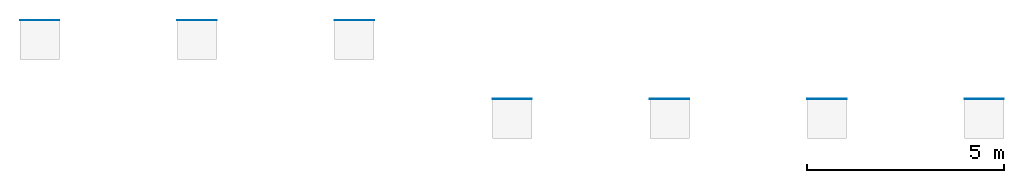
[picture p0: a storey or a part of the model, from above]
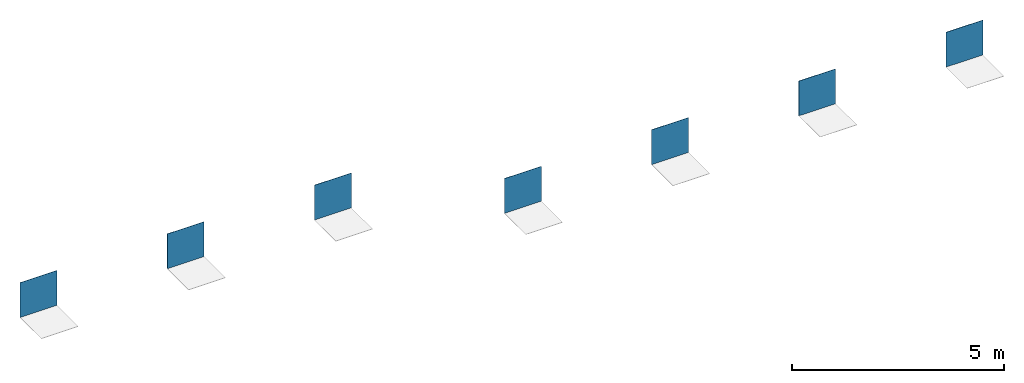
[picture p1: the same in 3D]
Properties of the parts of a building model (IFC2X3)

# File
Description: ViewDefinition [CoordinationView_V2.0]
Time: 2025-06-20T12:25:37
Written by: The EXPRESS Data Manager Version 5.02.0100.07 : 28 Aug 2013
Made in: 21.1.90.15 - Exporter 21.1.90.15 - Alternate UI 21.1.90.15
Comment: STEP Physical File produced by: The EXPRESS Data Manager Version 5.02.0100.07 : 28 Aug 2013 * Module: EDMstepFileFactory/EDMstandAlone * Creation date: Fri Jun 20 12:25:37 2025 * Host: STB002 * Database: C:\Users\LARISS~1\AppData\Local\Temp\234e31d9-e186-458c-9206-d387dea7a233\789adf32-d584-4b62-985c-cae58ec91f2d\ifc * Database version: 5507 * Database creation date: Fri Jun 20 12:25:37 2025 * Schema: IFC2X3 * Model: DataRepository.ifc * Model creation date: Fri Jun 20 12:25:37 2025 * Header model: DataRepository.ifc_HeaderModel * Header model creation date: Fri Jun 20 12:25:37 2025 * EDMuser: sdai-user * EDMgroup: sdai-group * License ID and type: 5605 : Permanent license. Expiry date: * EDMstepFileFactory options: 020000

# IfcSite, Default
RefLatitude: 42, 24, 53, 508911; RefLongitude: -71, -15, -29, -58837; RefElevation: 0 mm
Pset_ProductRequirements - Category: Project Information

# IfcBuilding
Pset_BuildingCommon - NumberOfStoreys: 1
Pset_ProductRequirements - Category: Project Information

# IfcBuildingStorey: Level:Level 1, Level 1
LongName: Level 1; Elevation: 0 mm
Pset_AirSideSystemInformation - Name: Level 1
Pset_ProductRequirements - Name: Level 1; Category: Levels

# IfcCovering: Floor:REVIGRÉS-LOCUS-DECOR-16,5X19-SOFT GRIP-HEXA FLOW BONE, Floor:REVIGRÉS-LOCUS-DECOR-16,5X19-SOFT GRIP-HEXA FLOW BONE:112826
In: Level 1
Type - PredefinedType: CLADDING; Material: REVIGRÉS-LOCUS-DECOR-16,5x19-SOFT GRIP-HEXA FLOW BONE 8.5 mm
Type - Pset_CoveringCommon - Material: Grés porcelânico
Type - Pset_ElementShading - Roughness: 304.8 mm
Type - Pset_ManufacturerTypeInformation - Manufacturer: REVIGRÉS
Type - Pset_ProductRequirements - Category: Floors
Type - IFC.REVIGRÉS-Dados do fabricante-Floor Covering - FabricanteURL: https://www.revigres.pt/; ReferenciaModelo: Locus; Acabamento: SOFT; Material: Grés porcelânico; IdentificadorDoOperadorEconomico: 501840856; GLNFabricante: https://www.revigres.pt/colecoes/locus; UrlFabricanteArtigo: https://www.revigres.pt/colecoes/locus; PaisOrigem: Portugal
Type - IFC.REVIGRÉS-Dados de desempenho-Floor Covering - Rectilinearidade: ± 0.2% máx.± 0.8 mm; Ortogonalidade: ± 0.2% máx.± 1.5 mm; PlanaridadeDaSuperficie: ± 0.3% máx. ± 1.8 mm; QualidadeDaSuperficie: Cumpre; AbsorcaoDeAgua: < 0.05%; CargaDeRuptura: > 45 N/mm²; ModuloDeRuptura: > 45 N/mm²; ResistenciaAFlexao: > 2000 N; ResistenciaAAbrasaoProfunda: < 120 mm³; ResistenciaAAbrasaoVidrados: ≤ 8,0x10-6 °C-1; DilatacaoTermicaLinear: ≤ 8,0x10-6 °C-1; ResistenciaAoChoqueTermico: Resiste; ResistenciaAFendilhagem: Cumpre; DurabilidadeInterior: Cumpre; DurabilidadeResistenciaAoGeloDegelo: Resiste; ResistenciaAoImpacto: R11; ResistenciaAoEscorregamentoDIN51130: R11; ResistenciaAoEscorregamentoDIN51097: A; ResistenciaAoEscorregamentoENV51097: A; ResistenciaAoEscorregamentoENV12633: Class 2; ResistenciaAoEscorregamentoBS7976: > 36; ResistenciaAoEscorregamentoEN177: ≥0,42; ResistenciaAoEscorregamentoANSIA1371: ≥0,42; ResistenciaAoDeslizamentoENV12633: Class 2; ResistenciaAoDeslizamentoBS7976: > 36; ResistenciaDaAderenciaArgamassas: Class A1FL/ Class A1; ResistenciaAsManchas: Class 5; ResistenciaAProdutosDomesticosDeLimpeza: 0; LibertacaoDeCadmio: 0; LibertacaoDeChumbo: 0
Type - IFC.REVIGRÉS-Dados de especificação-Floor Covering - VariacaoTonalidade: 3; NivelDeTrafego: 5; EPavimento: Sim; ERevestimento: Sim; EExterno: Sim
Type - IFC.REVIGRÉS-Dados geométricos-Floor Covering - AlturaNominal: 8.5 mm; ComprimentoNominal: 16.5 mm; LarguraNominal: 19 mm
Type - IFC.REVIGRÉS-Dados de sustentabilidade-Floor Covering - ItemEParcialmenteReciclado: 0; EnergiaTermicaExportada: 0; VolumeTotalDeResiduosRadioactivosEliminados: 0; ItemENovo: Sim; ItemEReciclado: Não; VidaÚtilEsperada: 50; SubstanciasPerigosas: Não; PotencialDeEsgotamentoAbioticoDosRecursosNaoFosseisMineraisEMetais: 0.000701; PotencialDeAquecimentoGlobalBiogenico: -0.48; CombustiveisFosseisComPotencialDeAquecimentoGlobal: 13.9; PotencialDeAquecimentoGlobalUsoDoSoloEMudancaDeUsoDoSolo: 0.0246; PotencialDeEutrofizacaoFraccaoDeNutrientesQueAtingemOCompartimentoFinalDeAguaDoce: 0.000189; PotencialDeEutrofizacaoFraccaoDeNutrientesQueAtingemOCompartimentoFinalMarinho: 0.0122; EnergiaRecuperada: 0.00739; ConsumoDeAguaDoce: 0.113; UtilizacaoLiquidaDeAguaDoce: 0.113; ResiduosPerigososEliminados: 0.00221; ResiduosNaoPerigososEliminados: 1.83; MassaTotalDeResiduosRadioactivosEliminados: 0.000394; EnergiaElectricaExportada: 1.55; MateriaisParaRecuperacaoDeEnergia: 0.00739; MateriaisParaReciclagem: 0.0253; UnidadeEPD: 1 m²
Type - IFC.REVIGRÉS-Dados gerais-Floor Covering - Nome: REVIGRÉS-LOCUS-DECOR- 16,5X19-SOFT GRIP-HEXA FLOW BONE; TipoProduto: Prensado a seco: grupo BIa UGL | Grés porcelânico técnico; NumeroDeRegistoDAP: EPD-REV-20240006-CCC1-EN; ReferenciaDAP: -; UrlDOP: -
Classification: C3010 (Uniformat)
Pset_CoveringCommon - TotalThickness: 8.5 mm
IFC.REVIGRÉS-Dados do fabricante-Floor Covering - Type: Floor: REVIGRÉS-LOCUS-DECOR-16,5X19-SOFT GRIP-HEXA FLOW BONE
IFC.REVIGRÉS-Dados de desempenho-Floor Covering - Type: Floor: REVIGRÉS-LOCUS-DECOR-16,5X19-SOFT GRIP-HEXA FLOW BONE
IFC.REVIGRÉS-Dados de especificação-Floor Covering - Type: Floor: REVIGRÉS-LOCUS-DECOR-16,5X19-SOFT GRIP-HEXA FLOW BONE
IFC.REVIGRÉS-Dados geométricos-Floor Covering - Type: Floor: REVIGRÉS-LOCUS-DECOR-16,5X19-SOFT GRIP-HEXA FLOW BONE
IFC.REVIGRÉS-Dados de sustentabilidade-Floor Covering - Type: Floor: REVIGRÉS-LOCUS-DECOR-16,5X19-SOFT GRIP-HEXA FLOW BONE

# IfcCovering: Floor:REVIGRÉS-LOCUS-DECOR-16,5X19-SOFT GRIP-HEXA FLOW SMOG, Floor:REVIGRÉS-LOCUS-DECOR-16,5X19-SOFT GRIP-HEXA FLOW SMOG:112834
In: Level 1
Type - PredefinedType: CLADDING; Material: REVIGRÉS-LOCUS-DECOR-16,5x19-SOFT GRIP-HEXA FLOW SMOG 8.5 mm
Type - Pset_CoveringCommon - Material: Grés porcelânico
Type - Pset_ElementShading - Roughness: 304.8 mm
Type - Pset_ManufacturerTypeInformation - Manufacturer: REVIGRÉS
Type - Pset_ProductRequirements - Category: Floors
Type - IFC.REVIGRÉS-Dados do fabricante-Floor Covering - FabricanteURL: https://www.revigres.pt/; ReferenciaModelo: Locus; Acabamento: SOFT; Material: Grés porcelânico; IdentificadorDoOperadorEconomico: 501840856; GLNFabricante: https://www.revigres.pt/colecoes/locus; UrlFabricanteArtigo: https://www.revigres.pt/colecoes/locus; PaisOrigem: Portugal
Type - IFC.REVIGRÉS-Dados de desempenho-Floor Covering - Rectilinearidade: ± 0.2% máx.± 0.8 mm; Ortogonalidade: ± 0.2% máx.± 1.5 mm; PlanaridadeDaSuperficie: ± 0.3% máx. ± 1.8 mm; QualidadeDaSuperficie: Cumpre; AbsorcaoDeAgua: < 0.05%; CargaDeRuptura: > 45 N/mm²; ModuloDeRuptura: > 45 N/mm²; ResistenciaAFlexao: > 2000 N; ResistenciaAAbrasaoProfunda: < 120 mm³; ResistenciaAAbrasaoVidrados: ≤ 8,0x10-6 °C-1; DilatacaoTermicaLinear: ≤ 8,0x10-6 °C-1; ResistenciaAoChoqueTermico: Resiste; ResistenciaAFendilhagem: Cumpre; DurabilidadeInterior: Cumpre; DurabilidadeResistenciaAoGeloDegelo: Resiste; ResistenciaAoImpacto: R11; ResistenciaAoEscorregamentoDIN51130: R11; ResistenciaAoEscorregamentoDIN51097: A; ResistenciaAoEscorregamentoENV51097: A; ResistenciaAoEscorregamentoENV12633: Class 2; ResistenciaAoEscorregamentoBS7976: > 36; ResistenciaAoEscorregamentoEN177: ≥0,42; ResistenciaAoEscorregamentoANSIA1371: ≥0,42; ResistenciaAoDeslizamentoENV12633: Class 2; ResistenciaAoDeslizamentoBS7976: > 36; ResistenciaDaAderenciaArgamassas: Class A1FL/ Class A1; ResistenciaAsManchas: Class 5; ResistenciaAProdutosDomesticosDeLimpeza: 0; LibertacaoDeCadmio: 0; LibertacaoDeChumbo: 0
Type - IFC.REVIGRÉS-Dados de especificação-Floor Covering - VariacaoTonalidade: 3; NivelDeTrafego: 5; EPavimento: Sim; ERevestimento: Sim; EExterno: Sim
Type - IFC.REVIGRÉS-Dados geométricos-Floor Covering - AlturaNominal: 8.5 mm; ComprimentoNominal: 16.5 mm; LarguraNominal: 19 mm
Type - IFC.REVIGRÉS-Dados de sustentabilidade-Floor Covering - EnergiaTermicaExportada: 0; VolumeTotalDeResiduosRadioactivosEliminados: 0; ItemENovo: Sim; ItemEParcialmenteReciclado: 0.29; ItemEReciclado: Sim; VidaÚtilEsperada: 50; SubstanciasPerigosas: Não; PotencialDeEsgotamentoAbioticoDosRecursosNaoFosseisMineraisEMetais: 0.000701; PotencialDeAquecimentoGlobalBiogenico: -0.48; CombustiveisFosseisComPotencialDeAquecimentoGlobal: 13.9; PotencialDeAquecimentoGlobalUsoDoSoloEMudancaDeUsoDoSolo: 0.0246; PotencialDeEutrofizacaoFraccaoDeNutrientesQueAtingemOCompartimentoFinalDeAguaDoce: 0.000189; PotencialDeEutrofizacaoFraccaoDeNutrientesQueAtingemOCompartimentoFinalMarinho: 0.0122; EnergiaRecuperada: 0.00739; ConsumoDeAguaDoce: 0.113; UtilizacaoLiquidaDeAguaDoce: 0.113; ResiduosPerigososEliminados: 0.00221; ResiduosNaoPerigososEliminados: 1.83; MassaTotalDeResiduosRadioactivosEliminados: 0.000394; EnergiaElectricaExportada: 1.55; MateriaisParaRecuperacaoDeEnergia: 0.00739; MateriaisParaReciclagem: 0.0253; UnidadeEPD: 1 m²
Type - IFC.REVIGRÉS-Dados gerais-Floor Covering - Nome: REVIGRÉS-LOCUS-DECOR- 16,5X19-SOFT GRIP-HEXA FLOW SMOG; TipoProduto: Prensado a seco: grupo BIa UGL | Grés porcelânico técnico; NumeroDeRegistoDAP: EPD-REV-20240006-CCC1-EN; ReferenciaDAP: -; UrlDOP: -
Classification: C3010 (Uniformat)
Pset_CoveringCommon - TotalThickness: 8.5 mm
IFC.REVIGRÉS-Dados do fabricante-Floor Covering - Type: Floor: REVIGRÉS-LOCUS-DECOR-16,5X19-SOFT GRIP-HEXA FLOW SMOG
IFC.REVIGRÉS-Dados de desempenho-Floor Covering - Type: Floor: REVIGRÉS-LOCUS-DECOR-16,5X19-SOFT GRIP-HEXA FLOW SMOG
IFC.REVIGRÉS-Dados de especificação-Floor Covering - Type: Floor: REVIGRÉS-LOCUS-DECOR-16,5X19-SOFT GRIP-HEXA FLOW SMOG
IFC.REVIGRÉS-Dados geométricos-Floor Covering - Type: Floor: REVIGRÉS-LOCUS-DECOR-16,5X19-SOFT GRIP-HEXA FLOW SMOG
IFC.REVIGRÉS-Dados de sustentabilidade-Floor Covering - Type: Floor: REVIGRÉS-LOCUS-DECOR-16,5X19-SOFT GRIP-HEXA FLOW SMOG

# IfcCovering: Floor:REVIGRÉS-LOCUS-DECOR-16,5X19-SOFT GRIP-HEXA SHADOW GRIS, Floor:REVIGRÉS-LOCUS-DECOR-16,5X19-SOFT GRIP-HEXA SHADOW GRIS:112842
In: Level 1
Type - PredefinedType: CLADDING; Material: REVIGRÉS-LOCUS-DECOR-16,5x19-SOFT GRIP-HEXA SHADOW GRIS 8.5 mm
Type - Pset_CoveringCommon - Material: Grés porcelânico
Type - Pset_ElementShading - Roughness: 304.8 mm
Type - Pset_ManufacturerTypeInformation - Manufacturer: REVIGRÉS
Type - Pset_ProductRequirements - Category: Floors
Type - IFC.REVIGRÉS-Dados do fabricante-Floor Covering - FabricanteURL: https://www.revigres.pt/; ReferenciaModelo: Locus; Acabamento: SOFT; Material: Grés porcelânico; IdentificadorDoOperadorEconomico: 501840856; GLNFabricante: https://www.revigres.pt/colecoes/locus; UrlFabricanteArtigo: https://www.revigres.pt/colecoes/locus; PaisOrigem: Portugal
Type - IFC.REVIGRÉS-Dados de desempenho-Floor Covering - Rectilinearidade: ± 0.2% máx.± 0.8 mm; Ortogonalidade: ± 0.2% máx.± 1.5 mm; PlanaridadeDaSuperficie: ± 0.3% máx. ± 1.8 mm; QualidadeDaSuperficie: Cumpre; AbsorcaoDeAgua: < 0.05%; CargaDeRuptura: > 45 N/mm²; ModuloDeRuptura: > 45 N/mm²; ResistenciaAFlexao: > 2000 N; ResistenciaAAbrasaoProfunda: < 120 mm³; ResistenciaAAbrasaoVidrados: ≤ 8,0x10-6 °C-1; DilatacaoTermicaLinear: ≤ 8,0x10-6 °C-1; ResistenciaAoChoqueTermico: Resiste; ResistenciaAFendilhagem: Cumpre; DurabilidadeInterior: Cumpre; DurabilidadeResistenciaAoGeloDegelo: Resiste; ResistenciaAoImpacto: R11; ResistenciaAoEscorregamentoDIN51130: R11; ResistenciaAoEscorregamentoDIN51097: A; ResistenciaAoEscorregamentoENV51097: A; ResistenciaAoEscorregamentoENV12633: Class 2; ResistenciaAoEscorregamentoBS7976: > 36; ResistenciaAoEscorregamentoEN177: ≥0,42; ResistenciaAoEscorregamentoANSIA1371: ≥0,42; ResistenciaAoDeslizamentoENV12633: Class 2; ResistenciaAoDeslizamentoBS7976: > 36; ResistenciaDaAderenciaArgamassas: Class A1FL/ Class A1; ResistenciaAsManchas: Class 5; ResistenciaAProdutosDomesticosDeLimpeza: 0; LibertacaoDeCadmio: 0; LibertacaoDeChumbo: 0
Type - IFC.REVIGRÉS-Dados de especificação-Floor Covering - VariacaoTonalidade: 3; NivelDeTrafego: 5; EPavimento: Sim; ERevestimento: Sim; EExterno: Sim
Type - IFC.REVIGRÉS-Dados geométricos-Floor Covering - AlturaNominal: 8.5 mm; ComprimentoNominal: 16.5 mm; LarguraNominal: 19 mm
Type - IFC.REVIGRÉS-Dados de sustentabilidade-Floor Covering - EnergiaTermicaExportada: 0; VolumeTotalDeResiduosRadioactivosEliminados: 0; ItemENovo: Sim; ItemEParcialmenteReciclado: 0.23; ItemEReciclado: Sim; VidaÚtilEsperada: 50; SubstanciasPerigosas: Não; PotencialDeEsgotamentoAbioticoDosRecursosNaoFosseisMineraisEMetais: 0.000701; PotencialDeAquecimentoGlobalBiogenico: -0.48; CombustiveisFosseisComPotencialDeAquecimentoGlobal: 13.9; PotencialDeAquecimentoGlobalUsoDoSoloEMudancaDeUsoDoSolo: 0.0246; PotencialDeEutrofizacaoFraccaoDeNutrientesQueAtingemOCompartimentoFinalDeAguaDoce: 0.000189; PotencialDeEutrofizacaoFraccaoDeNutrientesQueAtingemOCompartimentoFinalMarinho: 0.0122; EnergiaRecuperada: 0.00739; ConsumoDeAguaDoce: 0.113; UtilizacaoLiquidaDeAguaDoce: 0.113; ResiduosPerigososEliminados: 0.00221; ResiduosNaoPerigososEliminados: 1.83; MassaTotalDeResiduosRadioactivosEliminados: 0.000394; EnergiaElectricaExportada: 1.55; MateriaisParaRecuperacaoDeEnergia: 0.00739; MateriaisParaReciclagem: 0.0253; UnidadeEPD: 1 m²
Type - IFC.REVIGRÉS-Dados gerais-Floor Covering - Nome: REVIGRÉS-LOCUS-DECOR- 16,5X19-SOFT GRIP-HEXA SHADOW GRIS; TipoProduto: Prensado a seco: grupo BIa UGL | Grés porcelânico técnico; NumeroDeRegistoDAP: EPD-REV-20240006-CCC1-EN; ReferenciaDAP: -; UrlDOP: -
Classification: C3010 (Uniformat)
Pset_CoveringCommon - TotalThickness: 8.5 mm
IFC.REVIGRÉS-Dados do fabricante-Floor Covering - Type: Floor: REVIGRÉS-LOCUS-DECOR-16,5X19-SOFT GRIP-HEXA SHADOW GRIS
IFC.REVIGRÉS-Dados de desempenho-Floor Covering - Type: Floor: REVIGRÉS-LOCUS-DECOR-16,5X19-SOFT GRIP-HEXA SHADOW GRIS
IFC.REVIGRÉS-Dados de especificação-Floor Covering - Type: Floor: REVIGRÉS-LOCUS-DECOR-16,5X19-SOFT GRIP-HEXA SHADOW GRIS
IFC.REVIGRÉS-Dados geométricos-Floor Covering - Type: Floor: REVIGRÉS-LOCUS-DECOR-16,5X19-SOFT GRIP-HEXA SHADOW GRIS
IFC.REVIGRÉS-Dados de sustentabilidade-Floor Covering - Type: Floor: REVIGRÉS-LOCUS-DECOR-16,5X19-SOFT GRIP-HEXA SHADOW GRIS

# IfcCovering: Floor:REVIGRÉS-LOCUS-DECOR-30X30-SILK-STRATUS 9 LOCUS MIX BRICK, Floor:REVIGRÉS-LOCUS-DECOR-30X30-SILK-STRATUS 9 LOCUS MIX BRICK:133852
In: Level 1
Type - PredefinedType: CLADDING; Material: REVIGRÉS-LOCUS-DECOR-30X30-SILK-STRATUS 9 LOCUS MIX BRICK 8.5 mm
Type - Pset_CoveringCommon - Material: Grés porcelânico
Type - Pset_ElementShading - Roughness: 304.8 mm
Type - Pset_ManufacturerTypeInformation - Manufacturer: REVIGRÉS
Type - Pset_ProductRequirements - Category: Floors
Type - IFC.REVIGRÉS-Dados do fabricante-Floor Covering - FabricanteURL: https://www.revigres.pt/; ReferenciaModelo: Locus; Acabamento: SILK; Material: Grés porcelânico; IdentificadorDoOperadorEconomico: 501840856; GLNFabricante: https://www.revigres.pt/colecoes/locus; UrlFabricanteArtigo: https://www.revigres.pt/colecoes/locus; PaisOrigem: Portugal
Type - IFC.REVIGRÉS-Dados de desempenho-Floor Covering - Rectilinearidade: ± 0.2% máx.± 0.8 mm; Ortogonalidade: ± 0.2% máx.± 1.5 mm; PlanaridadeDaSuperficie: ± 0.3% máx. ± 1.8 mm; QualidadeDaSuperficie: Cumpre; AbsorcaoDeAgua: < 0.05%; CargaDeRuptura: > 45 N/mm²; ModuloDeRuptura: > 45 N/mm²; ResistenciaAFlexao: > 2000 N; ResistenciaAAbrasaoProfunda: < 120 mm³; ResistenciaAAbrasaoVidrados: ≤ 8,0x10-6 °C-1; DilatacaoTermicaLinear: ≤ 8,0x10-6 °C-1; ResistenciaAoChoqueTermico: Resiste; ResistenciaAFendilhagem: Cumpre; DurabilidadeInterior: Cumpre; DurabilidadeResistenciaAoGeloDegelo: Resiste; ResistenciaAoImpacto: R9; ResistenciaAoEscorregamentoDIN51130: R9; ResistenciaAoEscorregamentoDIN51097: A; ResistenciaAoEscorregamentoENV51097: A; ResistenciaAoEscorregamentoENV12633: Class 1; ResistenciaAoEscorregamentoBS7976: -; ResistenciaAoEscorregamentoEN177: ≥0,42; ResistenciaAoEscorregamentoANSIA1371: ≥0,42; ResistenciaAoDeslizamentoENV12633: Class 1; ResistenciaAoDeslizamentoBS7976: -; ResistenciaDaAderenciaArgamassas: Class A1FL/ Class A1; ResistenciaAsManchas: Class 5; ResistenciaAProdutosDomesticosDeLimpeza: 0; LibertacaoDeCadmio: 0; LibertacaoDeChumbo: 0
Type - IFC.REVIGRÉS-Dados de especificação-Floor Covering - VariacaoTonalidade: 3; NivelDeTrafego: 5; EPavimento: Sim; ERevestimento: Sim; EExterno: Sim
Type - IFC.REVIGRÉS-Dados geométricos-Floor Covering - AlturaNominal: 8.5 mm; ComprimentoNominal: 29.5 mm; LarguraNominal: 29.5 mm
Type - IFC.REVIGRÉS-Dados de sustentabilidade-Floor Covering - EnergiaTermicaExportada: 0; VolumeTotalDeResiduosRadioactivosEliminados: 0; ItemENovo: Sim; ItemEReciclado: 50; VidaÚtilEsperada: 50; SubstanciasPerigosas: Não; PotencialDeEsgotamentoAbioticoDosRecursosNaoFosseisMineraisEMetais: 0.000701; PotencialDeAquecimentoGlobalBiogenico: -0.48; CombustiveisFosseisComPotencialDeAquecimentoGlobal: 13.9; PotencialDeAquecimentoGlobalUsoDoSoloEMudancaDeUsoDoSolo: 0.0246; PotencialDeEutrofizacaoFraccaoDeNutrientesQueAtingemOCompartimentoFinalDeAguaDoce: 0.000189; PotencialDeEutrofizacaoFraccaoDeNutrientesQueAtingemOCompartimentoFinalMarinho: 0.0122; EnergiaRecuperada: 0.00739; ConsumoDeAguaDoce: 0.113; UtilizacaoLiquidaDeAguaDoce: 0.113; ResiduosPerigososEliminados: 0.00221; ResiduosNaoPerigososEliminados: 1.83; MassaTotalDeResiduosRadioactivosEliminados: 0.000394; EnergiaElectricaExportada: 1.55; MateriaisParaRecuperacaoDeEnergia: 0.00739; MateriaisParaReciclagem: 0.0253; UnidadeEPD: 1 m²
Type - IFC.REVIGRÉS-Dados gerais-Floor Covering - Nome: REVIGRÉS-LOCUS-DECOR-30x30-SILK-LOCUS MIX BRICK; TipoProduto: Prensado a seco: grupo BIa UGL | Grés porcelânico técnico; NumeroDeRegistoDAP: EPD-REV-20240006-CCC1-EN; ReferenciaDAP: -; UrlDOP: -
Classification: C3010 (Uniformat)
Pset_CoveringCommon - TotalThickness: 8.5 mm
IFC.REVIGRÉS-Dados do fabricante-Floor Covering - Type: Floor: REVIGRÉS-LOCUS-DECOR-30X30-SILK-STRATUS 9 LOCUS MIX BRICK
IFC.REVIGRÉS-Dados de desempenho-Floor Covering - Type: Floor: REVIGRÉS-LOCUS-DECOR-30X30-SILK-STRATUS 9 LOCUS MIX BRICK
IFC.REVIGRÉS-Dados de especificação-Floor Covering - Type: Floor: REVIGRÉS-LOCUS-DECOR-30X30-SILK-STRATUS 9 LOCUS MIX BRICK
IFC.REVIGRÉS-Dados geométricos-Floor Covering - Type: Floor: REVIGRÉS-LOCUS-DECOR-30X30-SILK-STRATUS 9 LOCUS MIX BRICK
IFC.REVIGRÉS-Dados de sustentabilidade-Floor Covering - Type: Floor: REVIGRÉS-LOCUS-DECOR-30X30-SILK-STRATUS 9 LOCUS MIX BRICK

# IfcCovering: Floor:REVIGRÉS-LOCUS-DECOR-30X30-SILK-STRATUS 9 LOCUS MIX COBALTO, Floor:REVIGRÉS-LOCUS-DECOR-30X30-SILK-STRATUS 9 LOCUS MIX COBALTO:133859
In: Level 1
Type - PredefinedType: CLADDING; Material: REVIGRÉS-LOCUS-DECOR-30X30-SILK-STRATUS 9 LOCUS MIX COBALTO 8.5 mm
Type - Pset_CoveringCommon - Material: Grés porcelânico
Type - Pset_ElementShading - Roughness: 304.8 mm
Type - Pset_ManufacturerTypeInformation - Manufacturer: REVIGRÉS
Type - Pset_ProductRequirements - Category: Floors
Type - IFC.REVIGRÉS-Dados do fabricante-Floor Covering - FabricanteURL: https://www.revigres.pt/; ReferenciaModelo: Locus; Acabamento: SILK; Material: Grés porcelânico; IdentificadorDoOperadorEconomico: 501840856; GLNFabricante: https://www.revigres.pt/colecoes/locus; UrlFabricanteArtigo: https://www.revigres.pt/colecoes/locus; PaisOrigem: Portugal
Type - IFC.REVIGRÉS-Dados de desempenho-Floor Covering - Rectilinearidade: ± 0.2% máx ± 1.0 mm; Ortogonalidade: ± 0.2% máx.± 1.5 mm; PlanaridadeDaSuperficie: ± 0.3% máx. ± 1.8 mm; QualidadeDaSuperficie: Cumpre; AbsorcaoDeAgua: < 0.05%; CargaDeRuptura: > 45 N/mm²; ModuloDeRuptura: > 45 N/mm²; ResistenciaAFlexao: > 2000 N; ResistenciaAAbrasaoProfunda: < 120 mm³; ResistenciaAAbrasaoVidrados: ≤ 8,0x10-6 °C-1; DilatacaoTermicaLinear: ≤ 8,0x10-6 °C-1; ResistenciaAoChoqueTermico: Resiste; ResistenciaAFendilhagem: Cumpre; DurabilidadeInterior: Cumpre; DurabilidadeResistenciaAoGeloDegelo: Resiste; ResistenciaAoImpacto: R9; ResistenciaAoEscorregamentoDIN51130: R9; ResistenciaAoEscorregamentoDIN51097: A; ResistenciaAoEscorregamentoENV51097: A; ResistenciaAoEscorregamentoENV12633: Class 1; ResistenciaAoEscorregamentoBS7976: -; ResistenciaAoEscorregamentoEN177: ≥0,42; ResistenciaAoEscorregamentoANSIA1371: ≥0,42; ResistenciaAoDeslizamentoENV12633: Class 1; ResistenciaAoDeslizamentoBS7976: -; ResistenciaDaAderenciaArgamassas: Class A1FL/ Class A1; ResistenciaAsManchas: Class 5; ResistenciaAProdutosDomesticosDeLimpeza: 0; LibertacaoDeCadmio: 0; LibertacaoDeChumbo: 0
Type - IFC.REVIGRÉS-Dados de especificação-Floor Covering - VariacaoTonalidade: 3; NivelDeTrafego: 5; EPavimento: Sim; ERevestimento: Sim; EExterno: Sim
Type - IFC.REVIGRÉS-Dados geométricos-Floor Covering - AlturaNominal: 8.5 mm; ComprimentoNominal: 29.5 mm; LarguraNominal: 29.5 mm
Type - IFC.REVIGRÉS-Dados de sustentabilidade-Floor Covering - EnergiaTermicaExportada: 0; VolumeTotalDeResiduosRadioactivosEliminados: 0; ItemENovo: Sim; ItemEReciclado: 50; VidaÚtilEsperada: 50; SubstanciasPerigosas: Não; PotencialDeEsgotamentoAbioticoDosRecursosNaoFosseisMineraisEMetais: 0.000701; PotencialDeAquecimentoGlobalBiogenico: -0.48; CombustiveisFosseisComPotencialDeAquecimentoGlobal: 13.9; PotencialDeAquecimentoGlobalUsoDoSoloEMudancaDeUsoDoSolo: 0.0246; PotencialDeEutrofizacaoFraccaoDeNutrientesQueAtingemOCompartimentoFinalDeAguaDoce: 0.000189; PotencialDeEutrofizacaoFraccaoDeNutrientesQueAtingemOCompartimentoFinalMarinho: 0.0122; EnergiaRecuperada: 0.00739; ConsumoDeAguaDoce: 0.113; UtilizacaoLiquidaDeAguaDoce: 0.113; ResiduosPerigososEliminados: 0.00221; ResiduosNaoPerigososEliminados: 1.83; MassaTotalDeResiduosRadioactivosEliminados: 0.000394; EnergiaElectricaExportada: 1.55; MateriaisParaRecuperacaoDeEnergia: 0.00739; MateriaisParaReciclagem: 0.0253; UnidadeEPD: 1 m²
Type - IFC.REVIGRÉS-Dados gerais-Floor Covering - Nome: REVIGRÉS-LOCUS-DECOR-30x30-SILK-LOCUS MIX COBALTO; TipoProduto: Prensado a seco: grupo BIa UGL | Grés porcelânico técnico; NumeroDeRegistoDAP: EPD-REV-20240006-CCC1-EN; ReferenciaDAP: -; UrlDOP: -
Classification: C3010 (Uniformat)
Pset_CoveringCommon - TotalThickness: 8.5 mm
IFC.REVIGRÉS-Dados do fabricante-Floor Covering - Type: Floor: REVIGRÉS-LOCUS-DECOR-30X30-SILK-STRATUS 9 LOCUS MIX COBALTO
IFC.REVIGRÉS-Dados de desempenho-Floor Covering - Type: Floor: REVIGRÉS-LOCUS-DECOR-30X30-SILK-STRATUS 9 LOCUS MIX COBALTO
IFC.REVIGRÉS-Dados de especificação-Floor Covering - Type: Floor: REVIGRÉS-LOCUS-DECOR-30X30-SILK-STRATUS 9 LOCUS MIX COBALTO
IFC.REVIGRÉS-Dados geométricos-Floor Covering - Type: Floor: REVIGRÉS-LOCUS-DECOR-30X30-SILK-STRATUS 9 LOCUS MIX COBALTO
IFC.REVIGRÉS-Dados de sustentabilidade-Floor Covering - Type: Floor: REVIGRÉS-LOCUS-DECOR-30X30-SILK-STRATUS 9 LOCUS MIX COBALTO

# IfcCovering: Floor:REVIGRÉS-LOCUS-DECOR-30X30-SILK-STRATUS 9 LOCUS MIX OCRE, Floor:REVIGRÉS-LOCUS-DECOR-30X30-SILK-STRATUS 9 LOCUS MIX OCRE:133874
In: Level 1
Type - PredefinedType: CLADDING; Material: REVIGRÉS-LOCUS-DECOR-30X30-SILK-STRATUS 9 LOCUS MIX OCRE 8.5 mm
Type - Pset_CoveringCommon - Material: Grés porcelânico
Type - Pset_ElementShading - Roughness: 304.8 mm
Type - Pset_ManufacturerTypeInformation - Manufacturer: REVIGRÉS
Type - Pset_ProductRequirements - Category: Floors
Type - IFC.REVIGRÉS-Dados do fabricante-Floor Covering - FabricanteURL: https://www.revigres.pt/; ReferenciaModelo: Locus; Acabamento: SILK; Material: Grés porcelânico; IdentificadorDoOperadorEconomico: 501840856; GLNFabricante: https://www.revigres.pt/colecoes/locus; UrlFabricanteArtigo: https://www.revigres.pt/colecoes/locus; PaisOrigem: Portugal
Type - IFC.REVIGRÉS-Dados de desempenho-Floor Covering - Rectilinearidade: ± 0.2% máx ± 1.0 mm; Ortogonalidade: ± 0.2% máx.± 1.5 mm; PlanaridadeDaSuperficie: ± 0.3% máx. ± 1.8 mm; QualidadeDaSuperficie: Cumpre; AbsorcaoDeAgua: < 0.05%; CargaDeRuptura: > 45 N/mm²; ModuloDeRuptura: > 45 N/mm²; ResistenciaAFlexao: > 2000 N; ResistenciaAAbrasaoProfunda: < 120 mm³; ResistenciaAAbrasaoVidrados: ≤ 8,0x10-6 °C-1; DilatacaoTermicaLinear: ≤ 8,0x10-6 °C-1; ResistenciaAoChoqueTermico: Resiste; ResistenciaAFendilhagem: Cumpre; DurabilidadeInterior: Cumpre; DurabilidadeResistenciaAoGeloDegelo: Resiste; ResistenciaAoImpacto: R9; ResistenciaAoEscorregamentoDIN51130: R9; ResistenciaAoEscorregamentoDIN51097: A; ResistenciaAoEscorregamentoENV51097: A; ResistenciaAoEscorregamentoENV12633: Class 1; ResistenciaAoEscorregamentoBS7976: -; ResistenciaAoEscorregamentoEN177: ≥0,42; ResistenciaAoEscorregamentoANSIA1371: ≥0,42; ResistenciaAoDeslizamentoENV12633: Class 1; ResistenciaAoDeslizamentoBS7976: -; ResistenciaDaAderenciaArgamassas: Class A1FL/ Class A1; ResistenciaAsManchas: Class 5; ResistenciaAProdutosDomesticosDeLimpeza: 0; LibertacaoDeCadmio: 0; LibertacaoDeChumbo: 0
Type - IFC.REVIGRÉS-Dados de especificação-Floor Covering - VariacaoTonalidade: 3; NivelDeTrafego: 5; EPavimento: Sim; ERevestimento: Sim; EExterno: Sim
Type - IFC.REVIGRÉS-Dados geométricos-Floor Covering - AlturaNominal: 8.5 mm; ComprimentoNominal: 29.5 mm; LarguraNominal: 29.5 mm
Type - IFC.REVIGRÉS-Dados de sustentabilidade-Floor Covering - EnergiaTermicaExportada: 0; VolumeTotalDeResiduosRadioactivosEliminados: 0; ItemENovo: Sim; ItemEReciclado: 50; VidaÚtilEsperada: 50; SubstanciasPerigosas: Não; PotencialDeEsgotamentoAbioticoDosRecursosNaoFosseisMineraisEMetais: 0.000701; PotencialDeAquecimentoGlobalBiogenico: -0.48; CombustiveisFosseisComPotencialDeAquecimentoGlobal: 13.9; PotencialDeAquecimentoGlobalUsoDoSoloEMudancaDeUsoDoSolo: 0.0246; PotencialDeEutrofizacaoFraccaoDeNutrientesQueAtingemOCompartimentoFinalDeAguaDoce: 0.000189; PotencialDeEutrofizacaoFraccaoDeNutrientesQueAtingemOCompartimentoFinalMarinho: 0.0122; EnergiaRecuperada: 0.00739; ConsumoDeAguaDoce: 0.113; UtilizacaoLiquidaDeAguaDoce: 0.113; ResiduosPerigososEliminados: 0.00221; ResiduosNaoPerigososEliminados: 1.83; MassaTotalDeResiduosRadioactivosEliminados: 0.000394; EnergiaElectricaExportada: 1.55; MateriaisParaRecuperacaoDeEnergia: 0.00739; MateriaisParaReciclagem: 0.0253; UnidadeEPD: 1 m²
Type - IFC.REVIGRÉS-Dados gerais-Floor Covering - Nome: REVIGRÉS-LOCUS-DECOR-30x30-SILK-LOCUS MIX OCRE; TipoProduto: Prensado a seco: grupo BIa UGL | Grés porcelânico técnico; NumeroDeRegistoDAP: EPD-REV-20240006-CCC1-EN; ReferenciaDAP: -; UrlDOP: -
Classification: C3010 (Uniformat)
Pset_CoveringCommon - TotalThickness: 8.5 mm
IFC.REVIGRÉS-Dados do fabricante-Floor Covering - Type: Floor: REVIGRÉS-LOCUS-DECOR-30X30-SILK-STRATUS 9 LOCUS MIX OCRE
IFC.REVIGRÉS-Dados de desempenho-Floor Covering - Type: Floor: REVIGRÉS-LOCUS-DECOR-30X30-SILK-STRATUS 9 LOCUS MIX OCRE
IFC.REVIGRÉS-Dados de especificação-Floor Covering - Type: Floor: REVIGRÉS-LOCUS-DECOR-30X30-SILK-STRATUS 9 LOCUS MIX OCRE
IFC.REVIGRÉS-Dados geométricos-Floor Covering - Type: Floor: REVIGRÉS-LOCUS-DECOR-30X30-SILK-STRATUS 9 LOCUS MIX OCRE
IFC.REVIGRÉS-Dados de sustentabilidade-Floor Covering - Type: Floor: REVIGRÉS-LOCUS-DECOR-30X30-SILK-STRATUS 9 LOCUS MIX OCRE

# IfcCovering: Floor:REVIGRÉS-LOCUS-DECOR-30X30-SILK-STRATUS 9 LOCUS MIX OLIVA, Floor:REVIGRÉS-LOCUS-DECOR-30X30-SILK-STRATUS 9 LOCUS MIX OLIVA:133866
In: Level 1
Type - PredefinedType: CLADDING; Material: REVIGRÉS-LOCUS-DECOR-30X30-SILK-STRATUS 9 LOCUS MIX OLIVA 8.5 mm
Type - Pset_CoveringCommon - Material: Grés porcelânico
Type - Pset_ElementShading - Roughness: 304.8 mm
Type - Pset_ManufacturerTypeInformation - Manufacturer: REVIGRÉS
Type - Pset_ProductRequirements - Category: Floors
Type - IFC.REVIGRÉS-Dados do fabricante-Floor Covering - FabricanteURL: https://www.revigres.pt/; ReferenciaModelo: Locus; Acabamento: SILK; Material: Grés porcelânico; IdentificadorDoOperadorEconomico: 501840856; GLNFabricante: https://www.revigres.pt/colecoes/locus; UrlFabricanteArtigo: https://www.revigres.pt/colecoes/locus; PaisOrigem: Portugal
Type - IFC.REVIGRÉS-Dados de desempenho-Floor Covering - Rectilinearidade: ± 0.2% máx ± 1.0 mm; Ortogonalidade: ± 0.2% máx.± 1.5 mm; PlanaridadeDaSuperficie: ± 0.3% máx. ± 1.8 mm; QualidadeDaSuperficie: Cumpre; AbsorcaoDeAgua: < 0.05%; CargaDeRuptura: > 45 N/mm²; ModuloDeRuptura: > 45 N/mm²; ResistenciaAFlexao: > 2000 N; ResistenciaAAbrasaoProfunda: < 120 mm³; ResistenciaAAbrasaoVidrados: ≤ 8,0x10-6 °C-1; DilatacaoTermicaLinear: ≤ 8,0x10-6 °C-1; ResistenciaAoChoqueTermico: Resiste; ResistenciaAFendilhagem: Cumpre; DurabilidadeInterior: Cumpre; DurabilidadeResistenciaAoGeloDegelo: Resiste; ResistenciaAoImpacto: R9; ResistenciaAoEscorregamentoDIN51130: R9; ResistenciaAoEscorregamentoDIN51097: A; ResistenciaAoEscorregamentoENV51097: A; ResistenciaAoEscorregamentoENV12633: Class 1; ResistenciaAoEscorregamentoBS7976: -; ResistenciaAoEscorregamentoEN177: ≥0,42; ResistenciaAoEscorregamentoANSIA1371: ≥0,42; ResistenciaAoDeslizamentoENV12633: Class 1; ResistenciaAoDeslizamentoBS7976: -; ResistenciaDaAderenciaArgamassas: Class A1FL/ Class A1; ResistenciaAsManchas: Class 5; ResistenciaAProdutosDomesticosDeLimpeza: 0; LibertacaoDeCadmio: 0; LibertacaoDeChumbo: 0
Type - IFC.REVIGRÉS-Dados de especificação-Floor Covering - VariacaoTonalidade: 3; NivelDeTrafego: 5; EPavimento: Sim; ERevestimento: Sim; EExterno: Sim
Type - IFC.REVIGRÉS-Dados geométricos-Floor Covering - AlturaNominal: 8.5 mm; ComprimentoNominal: 29.5 mm; LarguraNominal: 29.5 mm
Type - IFC.REVIGRÉS-Dados de sustentabilidade-Floor Covering - EnergiaTermicaExportada: 0; VolumeTotalDeResiduosRadioactivosEliminados: 0; ItemENovo: Sim; ItemEReciclado: 50; VidaÚtilEsperada: 50; SubstanciasPerigosas: Não; PotencialDeEsgotamentoAbioticoDosRecursosNaoFosseisMineraisEMetais: 0.000701; PotencialDeAquecimentoGlobalBiogenico: -0.48; CombustiveisFosseisComPotencialDeAquecimentoGlobal: 13.9; PotencialDeAquecimentoGlobalUsoDoSoloEMudancaDeUsoDoSolo: 0.0246; PotencialDeEutrofizacaoFraccaoDeNutrientesQueAtingemOCompartimentoFinalDeAguaDoce: 0.000189; PotencialDeEutrofizacaoFraccaoDeNutrientesQueAtingemOCompartimentoFinalMarinho: 0.0122; EnergiaRecuperada: 0.00739; ConsumoDeAguaDoce: 0.113; UtilizacaoLiquidaDeAguaDoce: 0.113; ResiduosPerigososEliminados: 0.00221; ResiduosNaoPerigososEliminados: 1.83; MassaTotalDeResiduosRadioactivosEliminados: 0.000394; EnergiaElectricaExportada: 1.55; MateriaisParaRecuperacaoDeEnergia: 0.00739; MateriaisParaReciclagem: 0.0253; UnidadeEPD: 1 m²
Type - IFC.REVIGRÉS-Dados gerais-Floor Covering - Nome: REVIGRÉS-LOCUS-DECOR-30x30-SILK-LOCUS MIX OLIVA; TipoProduto: Prensado a seco: grupo BIa UGL | Grés porcelânico técnico; NumeroDeRegistoDAP: EPD-REV-20240006-CCC1-EN; ReferenciaDAP: -; UrlDOP: -
Classification: C3010 (Uniformat)
Pset_CoveringCommon - TotalThickness: 8.5 mm
IFC.REVIGRÉS-Dados do fabricante-Floor Covering - Type: Floor: REVIGRÉS-LOCUS-DECOR-30X30-SILK-STRATUS 9 LOCUS MIX OLIVA
IFC.REVIGRÉS-Dados de desempenho-Floor Covering - Type: Floor: REVIGRÉS-LOCUS-DECOR-30X30-SILK-STRATUS 9 LOCUS MIX OLIVA
IFC.REVIGRÉS-Dados de especificação-Floor Covering - Type: Floor: REVIGRÉS-LOCUS-DECOR-30X30-SILK-STRATUS 9 LOCUS MIX OLIVA
IFC.REVIGRÉS-Dados geométricos-Floor Covering - Type: Floor: REVIGRÉS-LOCUS-DECOR-30X30-SILK-STRATUS 9 LOCUS MIX OLIVA
IFC.REVIGRÉS-Dados de sustentabilidade-Floor Covering - Type: Floor: REVIGRÉS-LOCUS-DECOR-30X30-SILK-STRATUS 9 LOCUS MIX OLIVA

# IfcWallStandardCase: Basic Wall:REVIGRÉS-LOCUS-DECOR-16,5X19-SOFT GRIP-HEXA FLOW BONE, Basic Wall:REVIGRÉS-LOCUS-DECOR-16,5X19-SOFT GRIP-HEXA FLOW BONE:112823
In: Level 1
Type - PredefinedType: STANDARD; Material: REVIGRÉS-LOCUS-DECOR-16,5x19-SOFT GRIP-HEXA FLOW BONE 8.5 mm
Type - Pset_ElementShading - Roughness: 304.8 mm
Type - Pset_ManufacturerTypeInformation - Manufacturer: REVIGRÉS
Type - Pset_ProductRequirements - Category: Walls
Type - Pset_ReinforcementBarPitchOfWall - Description: Concrete effect in wall and floor porcelain tile
Type - Pset_WallCommon - IsExternal: no
Type - IFC.REVIGRÉS-Dados do fabricante-Wall Covering - FabricanteURL: https://www.revigres.pt/; ReferenciaModelo: Locus; Acabamento: SOFT; Material: Grés porcelânico; IdentificadorDoOperadorEconomico: 501840856; UrlFabricanteArtigo: https://www.revigres.pt/colecoes/locus; PaisOrigem: Portugal
Type - IFC.REVIGRÉS-Dados de desempenho-Wall Covering - Rectilinearidade: ± 0.2% máx.± 0.8 mm; Ortogonalidade: ± 0.2% máx.± 1.5 mm; PlanaridadeDaSuperficie: ± 0.3% máx. ± 1.8 mm; QualidadeDaSuperficie: Cumpre; AbsorcaoDeAgua: < 0.05%; ModuloDeRuptura: > 45 N/mm²; ResistenciaAFlexao: > 2000 N; ResistenciaAAbrasaoProfunda: < 120 mm³; DilatacaoTermicaLinear: ≤ 8,0x10-6 °C-1; ResistenciaAoChoqueTermico: Resiste; DurabilidadeInterior: Cumpre; DurabilidadeResistenciaAoGeloDegelo: Resiste; ResistenciaAoEscorregamentoDIN51130: R11; ResistenciaAoEscorregamentoDIN51097: A; ResistenciaAoEscorregamentoENV51097: A; ResistenciaAoEscorregamentoENV12633: Class 2; ResistenciaAoEscorregamentoBS7976: > 36; ResistenciaAoEscorregamentoANSIA1371: ≥0,42; ResistenciaAoDeslizamentoENV12633: Class 2; ResistenciaAoDeslizamentoBS7976: > 36; ResistenciaAsManchas: Class 5; LibertacaoDeCadmio: 0; LibertacaoDeChumbo: 0
Type - IFC.REVIGRÉS-Dados de especificação-Wall Covering - VariacaoTonalidade: 3; NivelDeTrafego: 5; EPavimento: Sim; ERevestimento: Sim; EExterno: Sim
Type - IFC.REVIGRÉS-Dados geométricos-Wall Covering - AlturaNominal: 8.5 mm; ComprimentoNominal: 16.5 mm; LarguraNominal: 19 mm
Type - IFC.REVIGRÉS-Dados de sustentabilidade-Wall Covering - ItemENovo: Sim; ItemEParcialmenteReciclado: 0; ItemEReciclado: Não; VidaÚtilEsperada: 50; SubstanciasPerigosas: Não; PotencialDeEsgotamentoAbioticoDosRecursosNaoFosseisMineraisEMetais: 0.000701; PotencialDeAquecimentoGlobalBiogenico: -0.48; CombustiveisFosseisComPotencialDeAquecimentoGlobal: 13.9; PotencialDeAquecimentoGlobalUsoDoSoloEMudancaDeUsoDoSolo: 0.0246; PotencialDeEutrofizacaoFraccaoDeNutrientesQueAtingemOCompartimentoFinalDeAguaDoce: 0.000189; PotencialDeEutrofizacaoFraccaoDeNutrientesQueAtingemOCompartimentoFinalMarinho: 0.0122; PotencialPrivacaoDeAguaConsumoDeAguaPonderado: 4.5; EnergiaRecuperada: 0.00739; ConsumoDeAguaDoce: 0.113; UtilizacaoLiquidaDeAguaDoce: 0.113; ResiduosPerigososEliminados: 0.00221; ResiduosNaoPerigososEliminados: 1.83; MassaTotalDeResiduosRadioactivosEliminados: 0.000394; EnergiaElectricaExportada: 1.55; EnergiaTermicaExportada: 0; MateriaisParaRecuperacaoDeEnergia: 0.00739; MateriaisParaReciclagem: 0.0253; UnidadeEPD: 1 m²
Type - IFC.REVIGRÉS-Dados gerais-Wall Covering - Nome: REVIGRÉS-LOCUS-DECOR- 16,5X19-SOFT GRIP-HEXA FLOW BONE; TipoProduto: Prensado a seco: grupo BIa UGL | Grés porcelânico técnico; NumeroDeRegistoDAP: EPD-REV-20240006-CCC1-EN; ReferenciaDAP: -; UrlDOP: -
Classification: C3010 (Uniformat)
Pset_WallCommon - ExtendToStructure: no; LoadBearing: no
IFC.REVIGRÉS-Dados do fabricante-Wall Covering - Type: Basic Wall: REVIGRÉS-LOCUS-DECOR-16,5X19-SOFT GRIP-HEXA FLOW BONE
IFC.REVIGRÉS-Dados de desempenho-Wall Covering - Type: Basic Wall: REVIGRÉS-LOCUS-DECOR-16,5X19-SOFT GRIP-HEXA FLOW BONE
IFC.REVIGRÉS-Dados de especificação-Wall Covering - Type: Basic Wall: REVIGRÉS-LOCUS-DECOR-16,5X19-SOFT GRIP-HEXA FLOW BONE
IFC.REVIGRÉS-Dados geométricos-Wall Covering - Type: Basic Wall: REVIGRÉS-LOCUS-DECOR-16,5X19-SOFT GRIP-HEXA FLOW BONE
IFC.REVIGRÉS-Dados de sustentabilidade-Wall Covering - Type: Basic Wall: REVIGRÉS-LOCUS-DECOR-16,5X19-SOFT GRIP-HEXA FLOW BONE

# IfcWallStandardCase: Basic Wall:REVIGRÉS-LOCUS-DECOR-16,5X19-SOFT GRIP-HEXA FLOW SMOG, Basic Wall:REVIGRÉS-LOCUS-DECOR-16,5X19-SOFT GRIP-HEXA FLOW SMOG:112831
In: Level 1
Type - PredefinedType: STANDARD; Material: REVIGRÉS-LOCUS-DECOR-16,5x19-SOFT GRIP-HEXA FLOW SMOG 8.5 mm
Type - Pset_ElementShading - Roughness: 304.8 mm
Type - Pset_ManufacturerTypeInformation - Manufacturer: REVIGRÉS
Type - Pset_ProductRequirements - Category: Walls
Type - Pset_ReinforcementBarPitchOfWall - Description: Concrete effect in wall and floor porcelain tile
Type - Pset_WallCommon - IsExternal: no
Type - IFC.REVIGRÉS-Dados do fabricante-Wall Covering - FabricanteURL: https://www.revigres.pt/; ReferenciaModelo: Locus; Acabamento: SOFT; Material: Grés porcelânico; IdentificadorDoOperadorEconomico: 501840856; UrlFabricanteArtigo: https://www.revigres.pt/colecoes/locus; PaisOrigem: Portugal
Type - IFC.REVIGRÉS-Dados de desempenho-Wall Covering - Rectilinearidade: ± 0.2% máx.± 0.8 mm; Ortogonalidade: ± 0.2% máx.± 1.5 mm; PlanaridadeDaSuperficie: ± 0.3% máx. ± 1.8 mm; QualidadeDaSuperficie: Cumpre; AbsorcaoDeAgua: < 0.05%; ModuloDeRuptura: > 45 N/mm²; ResistenciaAFlexao: > 2000 N; ResistenciaAAbrasaoProfunda: < 120 mm³; DilatacaoTermicaLinear: ≤ 8,0x10-6 °C-1; ResistenciaAoChoqueTermico: Resiste; DurabilidadeInterior: Cumpre; DurabilidadeResistenciaAoGeloDegelo: Resiste; ResistenciaAoEscorregamentoDIN51130: R11; ResistenciaAoEscorregamentoDIN51097: A; ResistenciaAoEscorregamentoENV51097: A; ResistenciaAoEscorregamentoENV12633: Class 2; ResistenciaAoEscorregamentoBS7976: > 36; ResistenciaAoEscorregamentoANSIA1371: ≥0,42; ResistenciaAoDeslizamentoENV12633: Class 2; ResistenciaAoDeslizamentoBS7976: > 36; ResistenciaAsManchas: Class 5; LibertacaoDeCadmio: 0; LibertacaoDeChumbo: 0
Type - IFC.REVIGRÉS-Dados de especificação-Wall Covering - VariacaoTonalidade: 3; NivelDeTrafego: 5; EPavimento: Sim; ERevestimento: Sim; EExterno: Sim
Type - IFC.REVIGRÉS-Dados geométricos-Wall Covering - AlturaNominal: 8.5 mm; ComprimentoNominal: 16.5 mm; LarguraNominal: 19 mm
Type - IFC.REVIGRÉS-Dados de sustentabilidade-Wall Covering - PotencialPrivacaoDeAguaConsumoDeAguaPonderado: 4.5; EnergiaTermicaExportada: 0; ItemENovo: Sim; ItemEParcialmenteReciclado: 0.29; ItemEReciclado: Sim; VidaÚtilEsperada: 50; SubstanciasPerigosas: Não; PotencialDeEsgotamentoAbioticoDosRecursosNaoFosseisMineraisEMetais: 0.000701; PotencialDeAquecimentoGlobalBiogenico: -0.48; CombustiveisFosseisComPotencialDeAquecimentoGlobal: 13.9; PotencialDeAquecimentoGlobalUsoDoSoloEMudancaDeUsoDoSolo: 0.0246; PotencialDeEutrofizacaoFraccaoDeNutrientesQueAtingemOCompartimentoFinalDeAguaDoce: 0.000189; PotencialDeEutrofizacaoFraccaoDeNutrientesQueAtingemOCompartimentoFinalMarinho: 0.0122; EnergiaRecuperada: 0.00739; ConsumoDeAguaDoce: 0.113; UtilizacaoLiquidaDeAguaDoce: 0.113; ResiduosPerigososEliminados: 0.00221; ResiduosNaoPerigososEliminados: 1.83; MassaTotalDeResiduosRadioactivosEliminados: 0.000394; EnergiaElectricaExportada: 1.55; MateriaisParaRecuperacaoDeEnergia: 0.00739; MateriaisParaReciclagem: 0.0253; UnidadeEPD: 1 m²
Type - IFC.REVIGRÉS-Dados gerais-Wall Covering - Nome: REVIGRÉS-LOCUS-DECOR- 16,5X19-SOFT GRIP-HEXA FLOW SMOG; TipoProduto: Prensado a seco: grupo BIa UGL | Grés porcelânico técnico; NumeroDeRegistoDAP: EPD-REV-20240006-CCC1-EN; ReferenciaDAP: -; UrlDOP: -
Classification: C3010 (Uniformat)
Pset_WallCommon - ExtendToStructure: no; LoadBearing: no
IFC.REVIGRÉS-Dados do fabricante-Wall Covering - Type: Basic Wall: REVIGRÉS-LOCUS-DECOR-16,5X19-SOFT GRIP-HEXA FLOW SMOG
IFC.REVIGRÉS-Dados de desempenho-Wall Covering - Type: Basic Wall: REVIGRÉS-LOCUS-DECOR-16,5X19-SOFT GRIP-HEXA FLOW SMOG
IFC.REVIGRÉS-Dados de especificação-Wall Covering - Type: Basic Wall: REVIGRÉS-LOCUS-DECOR-16,5X19-SOFT GRIP-HEXA FLOW SMOG
IFC.REVIGRÉS-Dados geométricos-Wall Covering - Type: Basic Wall: REVIGRÉS-LOCUS-DECOR-16,5X19-SOFT GRIP-HEXA FLOW SMOG
IFC.REVIGRÉS-Dados de sustentabilidade-Wall Covering - Type: Basic Wall: REVIGRÉS-LOCUS-DECOR-16,5X19-SOFT GRIP-HEXA FLOW SMOG

# IfcWallStandardCase: Basic Wall:REVIGRÉS-LOCUS-DECOR-16,5X19-SOFT GRIP-HEXA SHADOW GRIS, Basic Wall:REVIGRÉS-LOCUS-DECOR-16,5X19-SOFT GRIP-HEXA SHADOW GRIS:112839
In: Level 1
Type - PredefinedType: STANDARD; Material: REVIGRÉS-LOCUS-DECOR-16,5x19-SOFT GRIP-HEXA SHADOW GRIS 8.5 mm
Type - Pset_ElementShading - Roughness: 304.8 mm
Type - Pset_ManufacturerTypeInformation - Manufacturer: REVIGRÉS
Type - Pset_ProductRequirements - Category: Walls
Type - Pset_ReinforcementBarPitchOfWall - Description: Concrete effect in wall and floor porcelain tile
Type - Pset_WallCommon - IsExternal: no
Type - IFC.REVIGRÉS-Dados do fabricante-Wall Covering - FabricanteURL: https://www.revigres.pt/; ReferenciaModelo: Locus; Acabamento: SOFT; Material: Grés porcelânico; IdentificadorDoOperadorEconomico: 501840856; UrlFabricanteArtigo: https://www.revigres.pt/colecoes/locus; PaisOrigem: Portugal
Type - IFC.REVIGRÉS-Dados de desempenho-Wall Covering - Rectilinearidade: ± 0.2% máx.± 0.8 mm; Ortogonalidade: ± 0.2% máx.± 1.5 mm; PlanaridadeDaSuperficie: ± 0.3% máx. ± 1.8 mm; QualidadeDaSuperficie: Cumpre; AbsorcaoDeAgua: < 0.05%; ModuloDeRuptura: > 45 N/mm²; ResistenciaAFlexao: > 2000 N; ResistenciaAAbrasaoProfunda: < 120 mm³; DilatacaoTermicaLinear: ≤ 8,0x10-6 °C-1; ResistenciaAoChoqueTermico: Resiste; DurabilidadeInterior: Cumpre; DurabilidadeResistenciaAoGeloDegelo: Resiste; ResistenciaAoEscorregamentoDIN51130: R11; ResistenciaAoEscorregamentoDIN51097: A; ResistenciaAoEscorregamentoENV51097: A; ResistenciaAoEscorregamentoENV12633: Class 2; ResistenciaAoEscorregamentoBS7976: > 36; ResistenciaAoEscorregamentoANSIA1371: ≥0,42; ResistenciaAoDeslizamentoENV12633: Class 2; ResistenciaAoDeslizamentoBS7976: > 36; ResistenciaAsManchas: Class 5; LibertacaoDeCadmio: 0; LibertacaoDeChumbo: 0
Type - IFC.REVIGRÉS-Dados de especificação-Wall Covering - VariacaoTonalidade: 3; NivelDeTrafego: 5; EPavimento: Sim; ERevestimento: Sim; EExterno: Sim
Type - IFC.REVIGRÉS-Dados geométricos-Wall Covering - AlturaNominal: 8.5 mm; ComprimentoNominal: 16.5 mm; LarguraNominal: 19 mm
Type - IFC.REVIGRÉS-Dados de sustentabilidade-Wall Covering - PotencialPrivacaoDeAguaConsumoDeAguaPonderado: 4.5; EnergiaTermicaExportada: 0; ItemENovo: Sim; ItemEParcialmenteReciclado: 0.23; ItemEReciclado: Sim; VidaÚtilEsperada: 50; SubstanciasPerigosas: Não; PotencialDeEsgotamentoAbioticoDosRecursosNaoFosseisMineraisEMetais: 0.000701; PotencialDeAquecimentoGlobalBiogenico: -0.48; CombustiveisFosseisComPotencialDeAquecimentoGlobal: 13.9; PotencialDeAquecimentoGlobalUsoDoSoloEMudancaDeUsoDoSolo: 0.0246; PotencialDeEutrofizacaoFraccaoDeNutrientesQueAtingemOCompartimentoFinalDeAguaDoce: 0.000189; PotencialDeEutrofizacaoFraccaoDeNutrientesQueAtingemOCompartimentoFinalMarinho: 0.0122; EnergiaRecuperada: 0.00739; ConsumoDeAguaDoce: 0.113; UtilizacaoLiquidaDeAguaDoce: 0.113; ResiduosPerigososEliminados: 0.00221; ResiduosNaoPerigososEliminados: 1.83; MassaTotalDeResiduosRadioactivosEliminados: 0.000394; EnergiaElectricaExportada: 1.55; MateriaisParaRecuperacaoDeEnergia: 0.00739; MateriaisParaReciclagem: 0.0253; UnidadeEPD: 1 m²
Type - IFC.REVIGRÉS-Dados gerais-Wall Covering - Nome: REVIGRÉS-LOCUS-DECOR- 16,5X19-SOFT GRIP-HEXA SHADOW GRIS; TipoProduto: Prensado a seco: grupo BIa UGL | Grés porcelânico técnico; NumeroDeRegistoDAP: EPD-REV-20240006-CCC1-EN; ReferenciaDAP: -; UrlDOP: -
Classification: C3010 (Uniformat)
Pset_WallCommon - ExtendToStructure: no; LoadBearing: no
IFC.REVIGRÉS-Dados do fabricante-Wall Covering - Type: Basic Wall: REVIGRÉS-LOCUS-DECOR-16,5X19-SOFT GRIP-HEXA SHADOW GRIS
IFC.REVIGRÉS-Dados de desempenho-Wall Covering - Type: Basic Wall: REVIGRÉS-LOCUS-DECOR-16,5X19-SOFT GRIP-HEXA SHADOW GRIS
IFC.REVIGRÉS-Dados de especificação-Wall Covering - Type: Basic Wall: REVIGRÉS-LOCUS-DECOR-16,5X19-SOFT GRIP-HEXA SHADOW GRIS
IFC.REVIGRÉS-Dados geométricos-Wall Covering - Type: Basic Wall: REVIGRÉS-LOCUS-DECOR-16,5X19-SOFT GRIP-HEXA SHADOW GRIS
IFC.REVIGRÉS-Dados de sustentabilidade-Wall Covering - Type: Basic Wall: REVIGRÉS-LOCUS-DECOR-16,5X19-SOFT GRIP-HEXA SHADOW GRIS

# IfcWallStandardCase: Basic Wall:REVIGRÉS-LOCUS-DECOR-30X30-SILK-STRATUS 9 LOCUS MIX BRICK, Basic Wall:REVIGRÉS-LOCUS-DECOR-30X30-SILK-STRATUS 9 LOCUS MIX BRICK:133847
In: Level 1
Type - PredefinedType: STANDARD; Material: REVIGRÉS-LOCUS-DECOR-30X30-SILK-STRATUS 9 LOCUS MIX BRICK 8.5 mm
Type - Pset_ElementShading - Roughness: 304.8 mm
Type - Pset_ManufacturerTypeInformation - Manufacturer: REVIGRÉS
Type - Pset_ProductRequirements - Category: Walls
Type - Pset_ReinforcementBarPitchOfWall - Description: Concrete effect in wall and floor porcelain tile
Type - Pset_WallCommon - IsExternal: no
Type - IFC.REVIGRÉS-Dados do fabricante-Wall Covering - FabricanteURL: https://www.revigres.pt/; ReferenciaModelo: Locus; Acabamento: SILK; Material: Grés porcelânico; IdentificadorDoOperadorEconomico: 501840856; UrlFabricanteArtigo: https://www.revigres.pt/colecoes/locus; PaisOrigem: Portugal
Type - IFC.REVIGRÉS-Dados de desempenho-Wall Covering - Rectilinearidade: ± 0.2% máx.± 0.8 mm; Ortogonalidade: ± 0.2% máx.± 1.5 mm; PlanaridadeDaSuperficie: ± 0.3% máx. ± 1.8 mm; QualidadeDaSuperficie: Cumpre; AbsorcaoDeAgua: < 0.05%; ModuloDeRuptura: > 45 N/mm²; ResistenciaAFlexao: > 2000 N; ResistenciaAAbrasaoProfunda: < 120 mm³; DilatacaoTermicaLinear: ≤ 8,0x10-6 °C-1; ResistenciaAoChoqueTermico: Resiste; DurabilidadeInterior: Cumpre; DurabilidadeResistenciaAoGeloDegelo: Resiste; ResistenciaAoEscorregamentoDIN51130: R9; ResistenciaAoEscorregamentoDIN51097: A; ResistenciaAoEscorregamentoENV51097: A; ResistenciaAoEscorregamentoENV12633: Class 1; ResistenciaAoEscorregamentoBS7976: -; ResistenciaAoEscorregamentoANSIA1371: ≥0,42; ResistenciaAoDeslizamentoENV12633: Class 1; ResistenciaAoDeslizamentoBS7976: -; ResistenciaAsManchas: Class 5; LibertacaoDeCadmio: 0; LibertacaoDeChumbo: 0
Type - IFC.REVIGRÉS-Dados de especificação-Wall Covering - VariacaoTonalidade: 3; NivelDeTrafego: 5; EPavimento: Sim; ERevestimento: Sim; EExterno: Sim
Type - IFC.REVIGRÉS-Dados geométricos-Wall Covering - AlturaNominal: 8.5 mm; ComprimentoNominal: 29.5 mm; LarguraNominal: 29.5 mm
Type - IFC.REVIGRÉS-Dados de sustentabilidade-Wall Covering - PotencialPrivacaoDeAguaConsumoDeAguaPonderado: 4.5; EnergiaTermicaExportada: 0; ItemENovo: Sim; VidaÚtilEsperada: 50; SubstanciasPerigosas: Não; PotencialDeEsgotamentoAbioticoDosRecursosNaoFosseisMineraisEMetais: 0.000701; PotencialDeAquecimentoGlobalBiogenico: -0.48; CombustiveisFosseisComPotencialDeAquecimentoGlobal: 13.9; PotencialDeAquecimentoGlobalUsoDoSoloEMudancaDeUsoDoSolo: 0.0246; PotencialDeEutrofizacaoFraccaoDeNutrientesQueAtingemOCompartimentoFinalDeAguaDoce: 0.000189; PotencialDeEutrofizacaoFraccaoDeNutrientesQueAtingemOCompartimentoFinalMarinho: 0.0122; EnergiaRecuperada: 0.00739; ConsumoDeAguaDoce: 0.113; UtilizacaoLiquidaDeAguaDoce: 0.113; ResiduosPerigososEliminados: 0.00221; ResiduosNaoPerigososEliminados: 1.83; MassaTotalDeResiduosRadioactivosEliminados: 0.000394; EnergiaElectricaExportada: 1.55; MateriaisParaRecuperacaoDeEnergia: 0.00739; MateriaisParaReciclagem: 0.0253; UnidadeEPD: 1 m²
Type - IFC.REVIGRÉS-Dados gerais-Wall Covering - Nome: REVIGRÉS-LOCUS-DECOR-30x30-SILK-LOCUS MIX BRICK; TipoProduto: Prensado a seco: grupo BIa UGL | Grés porcelânico técnico; NumeroDeRegistoDAP: EPD-REV-20240006-CCC1-EN; ReferenciaDAP: -; UrlDOP: -
Classification: C3010 (Uniformat)
Pset_WallCommon - ExtendToStructure: no; LoadBearing: no
IFC.REVIGRÉS-Dados do fabricante-Wall Covering - Type: Basic Wall: REVIGRÉS-LOCUS-DECOR-30X30-SILK-STRATUS 9 LOCUS MIX BRICK
IFC.REVIGRÉS-Dados de desempenho-Wall Covering - Type: Basic Wall: REVIGRÉS-LOCUS-DECOR-30X30-SILK-STRATUS 9 LOCUS MIX BRICK
IFC.REVIGRÉS-Dados de especificação-Wall Covering - Type: Basic Wall: REVIGRÉS-LOCUS-DECOR-30X30-SILK-STRATUS 9 LOCUS MIX BRICK
IFC.REVIGRÉS-Dados geométricos-Wall Covering - Type: Basic Wall: REVIGRÉS-LOCUS-DECOR-30X30-SILK-STRATUS 9 LOCUS MIX BRICK
IFC.REVIGRÉS-Dados de sustentabilidade-Wall Covering - Type: Basic Wall: REVIGRÉS-LOCUS-DECOR-30X30-SILK-STRATUS 9 LOCUS MIX BRICK

# IfcWallStandardCase: Basic Wall:REVIGRÉS-LOCUS-DECOR-30X30-SILK-STRATUS 9 LOCUS MIX COBALTO, Basic Wall:REVIGRÉS-LOCUS-DECOR-30X30-SILK-STRATUS 9 LOCUS MIX COBALTO:133848
In: Level 1
Type - PredefinedType: STANDARD; Material: REVIGRÉS-LOCUS-DECOR-30X30-SILK-STRATUS 9 LOCUS MIX COBALTO 8.5 mm
Type - Pset_ElementShading - Roughness: 304.8 mm
Type - Pset_ManufacturerTypeInformation - Manufacturer: REVIGRÉS
Type - Pset_ProductRequirements - Category: Walls
Type - Pset_ReinforcementBarPitchOfWall - Description: Concrete effect in wall and floor porcelain tile
Type - Pset_WallCommon - IsExternal: no
Type - IFC.REVIGRÉS-Dados do fabricante-Wall Covering - FabricanteURL: https://www.revigres.pt/; ReferenciaModelo: Locus; Acabamento: SILK; Material: Grés porcelânico; IdentificadorDoOperadorEconomico: 501840856; UrlFabricanteArtigo: https://www.revigres.pt/colecoes/locus; PaisOrigem: Portugal
Type - IFC.REVIGRÉS-Dados de desempenho-Wall Covering - Rectilinearidade: ± 0.2% máx ± 1.0 mm; Ortogonalidade: ± 0.2% máx.± 1.5 mm; PlanaridadeDaSuperficie: ± 0.3% máx. ± 1.8 mm; QualidadeDaSuperficie: Cumpre; AbsorcaoDeAgua: < 0.05%; ModuloDeRuptura: > 45 N/mm²; ResistenciaAFlexao: > 2000 N; ResistenciaAAbrasaoProfunda: < 120 mm³; DilatacaoTermicaLinear: ≤ 8,0x10-6 °C-1; ResistenciaAoChoqueTermico: Resiste; DurabilidadeInterior: Cumpre; DurabilidadeResistenciaAoGeloDegelo: Resiste; ResistenciaAoEscorregamentoDIN51130: R9; ResistenciaAoEscorregamentoDIN51097: A; ResistenciaAoEscorregamentoENV51097: A; ResistenciaAoEscorregamentoENV12633: Class 1; ResistenciaAoEscorregamentoBS7976: -; ResistenciaAoEscorregamentoANSIA1371: ≥0,42; ResistenciaAoDeslizamentoENV12633: Class 1; ResistenciaAoDeslizamentoBS7976: -; ResistenciaAsManchas: Class 5; LibertacaoDeCadmio: 0; LibertacaoDeChumbo: 0
Type - IFC.REVIGRÉS-Dados de especificação-Wall Covering - VariacaoTonalidade: 3; NivelDeTrafego: 5; EPavimento: Sim; ERevestimento: Sim; EExterno: Sim
Type - IFC.REVIGRÉS-Dados geométricos-Wall Covering - AlturaNominal: 8.5 mm; ComprimentoNominal: 29.5 mm; LarguraNominal: 29.5 mm
Type - IFC.REVIGRÉS-Dados de sustentabilidade-Wall Covering - PotencialPrivacaoDeAguaConsumoDeAguaPonderado: 4.5; EnergiaTermicaExportada: 0; ItemENovo: Sim; VidaÚtilEsperada: 50; SubstanciasPerigosas: Não; PotencialDeEsgotamentoAbioticoDosRecursosNaoFosseisMineraisEMetais: 0.000701; PotencialDeAquecimentoGlobalBiogenico: -0.48; CombustiveisFosseisComPotencialDeAquecimentoGlobal: 13.9; PotencialDeAquecimentoGlobalUsoDoSoloEMudancaDeUsoDoSolo: 0.0246; PotencialDeEutrofizacaoFraccaoDeNutrientesQueAtingemOCompartimentoFinalDeAguaDoce: 0.000189; PotencialDeEutrofizacaoFraccaoDeNutrientesQueAtingemOCompartimentoFinalMarinho: 0.0122; EnergiaRecuperada: 0.00739; ConsumoDeAguaDoce: 0.113; UtilizacaoLiquidaDeAguaDoce: 0.113; ResiduosPerigososEliminados: 0.00221; ResiduosNaoPerigososEliminados: 1.83; MassaTotalDeResiduosRadioactivosEliminados: 0.000394; EnergiaElectricaExportada: 1.55; MateriaisParaRecuperacaoDeEnergia: 0.00739; MateriaisParaReciclagem: 0.0253; UnidadeEPD: 1 m²
Type - IFC.REVIGRÉS-Dados gerais-Wall Covering - Nome: REVIGRÉS-LOCUS-DECOR-30x30-SILK-LOCUS MIX COBALTO; TipoProduto: Prensado a seco: grupo BIa UGL | Grés porcelânico técnico; NumeroDeRegistoDAP: EPD-REV-20240006-CCC1-EN; ReferenciaDAP: -; UrlDOP: -
Classification: C3010 (Uniformat)
Pset_WallCommon - ExtendToStructure: no; LoadBearing: no
IFC.REVIGRÉS-Dados do fabricante-Wall Covering - Type: Basic Wall: REVIGRÉS-LOCUS-DECOR-30X30-SILK-STRATUS 9 LOCUS MIX COBALTO
IFC.REVIGRÉS-Dados de desempenho-Wall Covering - Type: Basic Wall: REVIGRÉS-LOCUS-DECOR-30X30-SILK-STRATUS 9 LOCUS MIX COBALTO
IFC.REVIGRÉS-Dados de especificação-Wall Covering - Type: Basic Wall: REVIGRÉS-LOCUS-DECOR-30X30-SILK-STRATUS 9 LOCUS MIX COBALTO
IFC.REVIGRÉS-Dados geométricos-Wall Covering - Type: Basic Wall: REVIGRÉS-LOCUS-DECOR-30X30-SILK-STRATUS 9 LOCUS MIX COBALTO
IFC.REVIGRÉS-Dados de sustentabilidade-Wall Covering - Type: Basic Wall: REVIGRÉS-LOCUS-DECOR-30X30-SILK-STRATUS 9 LOCUS MIX COBALTO

# IfcWallStandardCase: Basic Wall:REVIGRÉS-LOCUS-DECOR-30X30-SILK-STRATUS 9 LOCUS MIX OCRE, Basic Wall:REVIGRÉS-LOCUS-DECOR-30X30-SILK-STRATUS 9 LOCUS MIX OCRE:133871
In: Level 1
Type - PredefinedType: STANDARD; Material: REVIGRÉS-LOCUS-DECOR-30X30-SILK-STRATUS 9 LOCUS MIX OCRE 8.5 mm
Type - Pset_ElementShading - Roughness: 304.8 mm
Type - Pset_ManufacturerTypeInformation - Manufacturer: REVIGRÉS
Type - Pset_ProductRequirements - Category: Walls
Type - Pset_ReinforcementBarPitchOfWall - Description: Concrete effect in wall and floor porcelain tile
Type - Pset_WallCommon - IsExternal: no
Type - IFC.REVIGRÉS-Dados do fabricante-Wall Covering - FabricanteURL: https://www.revigres.pt/; ReferenciaModelo: Locus; Acabamento: SILK; Material: Grés porcelânico; IdentificadorDoOperadorEconomico: 501840856; UrlFabricanteArtigo: https://www.revigres.pt/colecoes/locus; PaisOrigem: Portugal
Type - IFC.REVIGRÉS-Dados de desempenho-Wall Covering - Rectilinearidade: ± 0.2% máx ± 1.0 mm; Ortogonalidade: ± 0.2% máx.± 1.5 mm; PlanaridadeDaSuperficie: ± 0.3% máx. ± 1.8 mm; QualidadeDaSuperficie: Cumpre; AbsorcaoDeAgua: < 0.05%; ModuloDeRuptura: > 45 N/mm²; ResistenciaAFlexao: > 2000 N; ResistenciaAAbrasaoProfunda: < 120 mm³; DilatacaoTermicaLinear: ≤ 8,0x10-6 °C-1; ResistenciaAoChoqueTermico: Resiste; DurabilidadeInterior: Cumpre; DurabilidadeResistenciaAoGeloDegelo: Resiste; ResistenciaAoEscorregamentoDIN51130: R9; ResistenciaAoEscorregamentoDIN51097: A; ResistenciaAoEscorregamentoENV51097: A; ResistenciaAoEscorregamentoENV12633: Class 1; ResistenciaAoEscorregamentoBS7976: -; ResistenciaAoEscorregamentoANSIA1371: ≥0,42; ResistenciaAoDeslizamentoENV12633: Class 1; ResistenciaAoDeslizamentoBS7976: -; ResistenciaAsManchas: Class 5; LibertacaoDeCadmio: 0; LibertacaoDeChumbo: 0
Type - IFC.REVIGRÉS-Dados de especificação-Wall Covering - VariacaoTonalidade: 3; NivelDeTrafego: 5; EPavimento: Sim; ERevestimento: Sim; EExterno: Sim
Type - IFC.REVIGRÉS-Dados geométricos-Wall Covering - AlturaNominal: 8.5 mm; ComprimentoNominal: 29.5 mm; LarguraNominal: 29.5 mm
Type - IFC.REVIGRÉS-Dados de sustentabilidade-Wall Covering - PotencialPrivacaoDeAguaConsumoDeAguaPonderado: 4.5; EnergiaTermicaExportada: 0; ItemENovo: Sim; VidaÚtilEsperada: 50; SubstanciasPerigosas: Não; PotencialDeEsgotamentoAbioticoDosRecursosNaoFosseisMineraisEMetais: 0.000701; PotencialDeAquecimentoGlobalBiogenico: -0.48; CombustiveisFosseisComPotencialDeAquecimentoGlobal: 13.9; PotencialDeAquecimentoGlobalUsoDoSoloEMudancaDeUsoDoSolo: 0.0246; PotencialDeEutrofizacaoFraccaoDeNutrientesQueAtingemOCompartimentoFinalDeAguaDoce: 0.000189; PotencialDeEutrofizacaoFraccaoDeNutrientesQueAtingemOCompartimentoFinalMarinho: 0.0122; EnergiaRecuperada: 0.00739; ConsumoDeAguaDoce: 0.113; UtilizacaoLiquidaDeAguaDoce: 0.113; ResiduosPerigososEliminados: 0.00221; ResiduosNaoPerigososEliminados: 1.83; MassaTotalDeResiduosRadioactivosEliminados: 0.000394; EnergiaElectricaExportada: 1.55; MateriaisParaRecuperacaoDeEnergia: 0.00739; MateriaisParaReciclagem: 0.0253; UnidadeEPD: 1 m²
Type - IFC.REVIGRÉS-Dados gerais-Wall Covering - Nome: REVIGRÉS-LOCUS-DECOR-30x30-SILK-LOCUS MIX OCRE; TipoProduto: Prensado a seco: grupo BIa UGL | Grés porcelânico técnico; NumeroDeRegistoDAP: EPD-REV-20240006-CCC1-EN; ReferenciaDAP: -; UrlDOP: -
Classification: C3010 (Uniformat)
Pset_WallCommon - ExtendToStructure: no; LoadBearing: no
IFC.REVIGRÉS-Dados do fabricante-Wall Covering - Type: Basic Wall: REVIGRÉS-LOCUS-DECOR-30X30-SILK-STRATUS 9 LOCUS MIX OCRE
IFC.REVIGRÉS-Dados de desempenho-Wall Covering - Type: Basic Wall: REVIGRÉS-LOCUS-DECOR-30X30-SILK-STRATUS 9 LOCUS MIX OCRE
IFC.REVIGRÉS-Dados de especificação-Wall Covering - Type: Basic Wall: REVIGRÉS-LOCUS-DECOR-30X30-SILK-STRATUS 9 LOCUS MIX OCRE
IFC.REVIGRÉS-Dados geométricos-Wall Covering - Type: Basic Wall: REVIGRÉS-LOCUS-DECOR-30X30-SILK-STRATUS 9 LOCUS MIX OCRE
IFC.REVIGRÉS-Dados de sustentabilidade-Wall Covering - Type: Basic Wall: REVIGRÉS-LOCUS-DECOR-30X30-SILK-STRATUS 9 LOCUS MIX OCRE

# IfcWallStandardCase: Basic Wall:REVIGRÉS-LOCUS-DECOR-30X30-SILK-STRATUS 9 LOCUS MIX OLIVA, Basic Wall:REVIGRÉS-LOCUS-DECOR-30X30-SILK-STRATUS 9 LOCUS MIX OLIVA:133849
In: Level 1
Type - PredefinedType: STANDARD; Material: REVIGRÉS-LOCUS-DECOR-30X30-SILK-STRATUS 9 LOCUS MIX OLIVA 8.5 mm
Type - Pset_ElementShading - Roughness: 304.8 mm
Type - Pset_ManufacturerTypeInformation - Manufacturer: REVIGRÉS
Type - Pset_ProductRequirements - Category: Walls
Type - Pset_ReinforcementBarPitchOfWall - Description: Concrete effect in wall and floor porcelain tile
Type - Pset_WallCommon - IsExternal: no
Type - IFC.REVIGRÉS-Dados do fabricante-Wall Covering - FabricanteURL: https://www.revigres.pt/; ReferenciaModelo: Locus; Acabamento: SILK; Material: Grés porcelânico; IdentificadorDoOperadorEconomico: 501840856; UrlFabricanteArtigo: https://www.revigres.pt/colecoes/locus; PaisOrigem: Portugal
Type - IFC.REVIGRÉS-Dados de desempenho-Wall Covering - Rectilinearidade: ± 0.2% máx ± 1.0 mm; Ortogonalidade: ± 0.2% máx.± 1.5 mm; PlanaridadeDaSuperficie: ± 0.3% máx. ± 1.8 mm; QualidadeDaSuperficie: Cumpre; AbsorcaoDeAgua: < 0.05%; ModuloDeRuptura: > 45 N/mm²; ResistenciaAFlexao: > 2000 N; ResistenciaAAbrasaoProfunda: < 120 mm³; DilatacaoTermicaLinear: ≤ 8,0x10-6 °C-1; ResistenciaAoChoqueTermico: Resiste; DurabilidadeInterior: Cumpre; DurabilidadeResistenciaAoGeloDegelo: Resiste; ResistenciaAoEscorregamentoDIN51130: R9; ResistenciaAoEscorregamentoDIN51097: A; ResistenciaAoEscorregamentoENV51097: A; ResistenciaAoEscorregamentoENV12633: Class 1; ResistenciaAoEscorregamentoBS7976: -; ResistenciaAoEscorregamentoANSIA1371: ≥0,42; ResistenciaAoDeslizamentoENV12633: Class 1; ResistenciaAoDeslizamentoBS7976: -; ResistenciaAsManchas: Class 5; LibertacaoDeCadmio: 0; LibertacaoDeChumbo: 0
Type - IFC.REVIGRÉS-Dados de especificação-Wall Covering - VariacaoTonalidade: 3; NivelDeTrafego: 5; EPavimento: Sim; ERevestimento: Sim; EExterno: Sim
Type - IFC.REVIGRÉS-Dados geométricos-Wall Covering - AlturaNominal: 8.5 mm; ComprimentoNominal: 29.5 mm; LarguraNominal: 29.5 mm
Type - IFC.REVIGRÉS-Dados de sustentabilidade-Wall Covering - PotencialPrivacaoDeAguaConsumoDeAguaPonderado: 4.5; EnergiaTermicaExportada: 0; ItemENovo: Sim; VidaÚtilEsperada: 50; SubstanciasPerigosas: Não; PotencialDeEsgotamentoAbioticoDosRecursosNaoFosseisMineraisEMetais: 0.000701; PotencialDeAquecimentoGlobalBiogenico: -0.48; CombustiveisFosseisComPotencialDeAquecimentoGlobal: 13.9; PotencialDeAquecimentoGlobalUsoDoSoloEMudancaDeUsoDoSolo: 0.0246; PotencialDeEutrofizacaoFraccaoDeNutrientesQueAtingemOCompartimentoFinalDeAguaDoce: 0.000189; PotencialDeEutrofizacaoFraccaoDeNutrientesQueAtingemOCompartimentoFinalMarinho: 0.0122; EnergiaRecuperada: 0.00739; ConsumoDeAguaDoce: 0.113; UtilizacaoLiquidaDeAguaDoce: 0.113; ResiduosPerigososEliminados: 0.00221; ResiduosNaoPerigososEliminados: 1.83; MassaTotalDeResiduosRadioactivosEliminados: 0.000394; EnergiaElectricaExportada: 1.55; MateriaisParaRecuperacaoDeEnergia: 0.00739; MateriaisParaReciclagem: 0.0253; UnidadeEPD: 1 m²
Type - IFC.REVIGRÉS-Dados gerais-Wall Covering - Nome: REVIGRÉS-LOCUS-DECOR-30x30-SILK-LOCUS MIX OLIVA; TipoProduto: Prensado a seco: grupo BIa UGL | Grés porcelânico técnico; NumeroDeRegistoDAP: EPD-REV-20240006-CCC1-EN; ReferenciaDAP: -; UrlDOP: -
Classification: C3010 (Uniformat)
Pset_WallCommon - ExtendToStructure: no; LoadBearing: no
IFC.REVIGRÉS-Dados do fabricante-Wall Covering - Type: Basic Wall: REVIGRÉS-LOCUS-DECOR-30X30-SILK-STRATUS 9 LOCUS MIX OLIVA
IFC.REVIGRÉS-Dados de desempenho-Wall Covering - Type: Basic Wall: REVIGRÉS-LOCUS-DECOR-30X30-SILK-STRATUS 9 LOCUS MIX OLIVA
IFC.REVIGRÉS-Dados de especificação-Wall Covering - Type: Basic Wall: REVIGRÉS-LOCUS-DECOR-30X30-SILK-STRATUS 9 LOCUS MIX OLIVA
IFC.REVIGRÉS-Dados geométricos-Wall Covering - Type: Basic Wall: REVIGRÉS-LOCUS-DECOR-30X30-SILK-STRATUS 9 LOCUS MIX OLIVA
IFC.REVIGRÉS-Dados de sustentabilidade-Wall Covering - Type: Basic Wall: REVIGRÉS-LOCUS-DECOR-30X30-SILK-STRATUS 9 LOCUS MIX OLIVA
